VERSION 5.7 ;
  NOWIREEXTENSIONATPIN ON ;
  DIVIDERCHAR "/" ;
  BUSBITCHARS "[]" ;
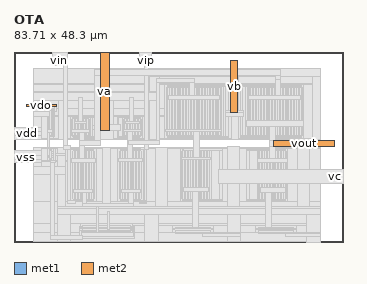
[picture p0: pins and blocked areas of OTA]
MACRO OTA
  CLASS BLOCK ;
  FOREIGN OTA ;
  ORIGIN 1.020 6.080 ;
  SIZE 83.710 BY 48.300 ;
  PIN vdd
    ANTENNADIFFAREA 38.813801 ;
    PORT
      LAYER met1 ;
        RECT 0.950 20.980 1.950 21.980 ;
    END
  END vdd
  PIN vss
    ANTENNADIFFAREA 53.217800 ;
    PORT
      LAYER met1 ;
        RECT 0.980 14.960 1.980 15.960 ;
    END
  END vss
  PIN vip
    ANTENNAGATEAREA 38.399998 ;
    PORT
      LAYER met1 ;
        RECT 31.990 39.990 32.990 40.990 ;
    END
  END vip
  PIN vin
    ANTENNAGATEAREA 38.399998 ;
    PORT
      LAYER met1 ;
        RECT 10.040 40.000 11.040 41.000 ;
    END
  END vin
  PIN vc
    ANTENNAGATEAREA 96.000000 ;
    PORT
      LAYER met1 ;
        RECT 79.970 10.010 80.970 11.010 ;
    END
  END vc
  PIN va
    ANTENNAGATEAREA 19.199999 ;
    PORT
      LAYER met2 ;
        RECT 20.870 22.270 23.230 42.000 ;
    END
  END va
  PIN vb
    ANTENNAGATEAREA 192.000000 ;
    PORT
      LAYER met2 ;
        RECT 54.060 26.800 55.760 40.130 ;
    END
  END vb
  PIN vout
    ANTENNADIFFAREA 59.160000 ;
    PORT
      LAYER met2 ;
        RECT 65.000 18.270 80.580 19.630 ;
    END
  END vout
  PIN vdo
    ANTENNAGATEAREA 2.400000 ;
    PORT
      LAYER met2 ;
        RECT 2.210 28.480 9.710 28.980 ;
    END
  END vdo
  OBS
      LAYER nwell ;
        RECT 7.020 20.005 9.380 28.195 ;
        RECT 12.995 20.005 18.805 26.195 ;
        RECT 26.205 19.995 32.015 26.185 ;
        RECT 36.995 19.995 52.465 34.185 ;
        RECT 57.540 19.995 73.010 34.185 ;
      LAYER pwell ;
        RECT 7.020 14.320 9.380 18.020 ;
        RECT 13.010 3.920 20.200 18.020 ;
        RECT 25.045 3.890 32.235 17.990 ;
        RECT 40.955 3.900 49.525 18.000 ;
        RECT 60.455 3.920 69.025 18.020 ;
        RECT 15.460 -4.090 29.560 -1.040 ;
        RECT 38.880 -4.000 49.980 -1.640 ;
        RECT 60.010 -3.965 71.110 -1.605 ;
      LAYER li1 ;
        RECT 3.990 38.020 7.390 38.030 ;
        RECT 3.990 38.000 37.360 38.020 ;
        RECT 3.990 34.170 76.970 38.000 ;
        RECT 3.990 33.835 76.990 34.170 ;
        RECT 3.990 27.820 37.360 33.835 ;
        RECT 37.975 33.325 38.375 33.495 ;
        RECT 38.665 33.325 39.065 33.495 ;
        RECT 39.355 33.325 39.755 33.495 ;
        RECT 40.045 33.325 40.445 33.495 ;
        RECT 40.735 33.325 41.135 33.495 ;
        RECT 41.425 33.325 41.825 33.495 ;
        RECT 42.115 33.325 42.515 33.495 ;
        RECT 42.805 33.325 43.205 33.495 ;
        RECT 43.495 33.325 43.895 33.495 ;
        RECT 44.185 33.325 44.585 33.495 ;
        RECT 44.875 33.325 45.275 33.495 ;
        RECT 45.565 33.325 45.965 33.495 ;
        RECT 46.255 33.325 46.655 33.495 ;
        RECT 46.945 33.325 47.345 33.495 ;
        RECT 47.635 33.325 48.035 33.495 ;
        RECT 48.325 33.325 48.725 33.495 ;
        RECT 49.015 33.325 49.415 33.495 ;
        RECT 49.705 33.325 50.105 33.495 ;
        RECT 50.395 33.325 50.795 33.495 ;
        RECT 51.085 33.325 51.485 33.495 ;
        RECT 3.990 20.355 7.390 27.820 ;
        RECT 8.000 27.335 8.400 27.505 ;
        RECT 7.770 21.080 7.940 27.120 ;
        RECT 8.460 21.080 8.630 27.120 ;
        RECT 9.000 26.110 37.345 27.820 ;
        RECT 9.000 25.840 37.360 26.110 ;
        RECT 8.000 20.695 8.400 20.865 ;
        RECT 9.000 20.355 13.345 25.840 ;
        RECT 18.440 25.835 37.360 25.840 ;
        RECT 13.975 25.335 14.375 25.505 ;
        RECT 14.665 25.335 15.065 25.505 ;
        RECT 15.355 25.335 15.755 25.505 ;
        RECT 16.045 25.335 16.445 25.505 ;
        RECT 16.735 25.335 17.135 25.505 ;
        RECT 17.425 25.335 17.825 25.505 ;
        RECT 13.745 21.080 13.915 25.120 ;
        RECT 14.435 21.080 14.605 25.120 ;
        RECT 15.125 21.080 15.295 25.120 ;
        RECT 15.815 21.080 15.985 25.120 ;
        RECT 16.505 21.080 16.675 25.120 ;
        RECT 17.195 21.080 17.365 25.120 ;
        RECT 17.885 21.080 18.055 25.120 ;
        RECT 13.975 20.695 14.375 20.865 ;
        RECT 14.665 20.695 15.065 20.865 ;
        RECT 15.355 20.695 15.755 20.865 ;
        RECT 16.045 20.695 16.445 20.865 ;
        RECT 16.735 20.695 17.135 20.865 ;
        RECT 17.425 20.695 17.825 20.865 ;
        RECT 18.440 20.355 26.555 25.835 ;
        RECT 27.185 25.325 27.585 25.495 ;
        RECT 27.875 25.325 28.275 25.495 ;
        RECT 28.565 25.325 28.965 25.495 ;
        RECT 29.255 25.325 29.655 25.495 ;
        RECT 29.945 25.325 30.345 25.495 ;
        RECT 30.635 25.325 31.035 25.495 ;
        RECT 26.955 21.070 27.125 25.110 ;
        RECT 27.645 21.070 27.815 25.110 ;
        RECT 28.335 21.070 28.505 25.110 ;
        RECT 29.025 21.070 29.195 25.110 ;
        RECT 29.715 21.070 29.885 25.110 ;
        RECT 30.405 21.070 30.575 25.110 ;
        RECT 31.095 21.070 31.265 25.110 ;
        RECT 27.185 20.685 27.585 20.855 ;
        RECT 27.875 20.685 28.275 20.855 ;
        RECT 28.565 20.685 28.965 20.855 ;
        RECT 29.255 20.685 29.655 20.855 ;
        RECT 29.945 20.685 30.345 20.855 ;
        RECT 30.635 20.685 31.035 20.855 ;
        RECT 3.990 20.345 26.555 20.355 ;
        RECT 31.630 20.345 37.360 25.835 ;
        RECT 37.745 21.070 37.915 33.110 ;
        RECT 38.435 21.070 38.605 33.110 ;
        RECT 39.125 21.070 39.295 33.110 ;
        RECT 39.815 21.070 39.985 33.110 ;
        RECT 40.505 21.070 40.675 33.110 ;
        RECT 41.195 21.070 41.365 33.110 ;
        RECT 41.885 21.070 42.055 33.110 ;
        RECT 42.575 21.070 42.745 33.110 ;
        RECT 43.265 21.070 43.435 33.110 ;
        RECT 43.955 21.070 44.125 33.110 ;
        RECT 44.645 21.070 44.815 33.110 ;
        RECT 45.335 21.070 45.505 33.110 ;
        RECT 46.025 21.070 46.195 33.110 ;
        RECT 46.715 21.070 46.885 33.110 ;
        RECT 47.405 21.070 47.575 33.110 ;
        RECT 48.095 21.070 48.265 33.110 ;
        RECT 48.785 21.070 48.955 33.110 ;
        RECT 49.475 21.070 49.645 33.110 ;
        RECT 50.165 21.070 50.335 33.110 ;
        RECT 50.855 21.070 51.025 33.110 ;
        RECT 51.545 21.070 51.715 33.110 ;
        RECT 37.975 20.685 38.375 20.855 ;
        RECT 38.665 20.685 39.065 20.855 ;
        RECT 39.355 20.685 39.755 20.855 ;
        RECT 40.045 20.685 40.445 20.855 ;
        RECT 40.735 20.685 41.135 20.855 ;
        RECT 41.425 20.685 41.825 20.855 ;
        RECT 42.115 20.685 42.515 20.855 ;
        RECT 42.805 20.685 43.205 20.855 ;
        RECT 43.495 20.685 43.895 20.855 ;
        RECT 44.185 20.685 44.585 20.855 ;
        RECT 44.875 20.685 45.275 20.855 ;
        RECT 45.565 20.685 45.965 20.855 ;
        RECT 46.255 20.685 46.655 20.855 ;
        RECT 46.945 20.685 47.345 20.855 ;
        RECT 47.635 20.685 48.035 20.855 ;
        RECT 48.325 20.685 48.725 20.855 ;
        RECT 49.015 20.685 49.415 20.855 ;
        RECT 49.705 20.685 50.105 20.855 ;
        RECT 50.395 20.685 50.795 20.855 ;
        RECT 51.085 20.685 51.485 20.855 ;
        RECT 52.110 20.345 57.890 33.835 ;
        RECT 58.520 33.325 58.920 33.495 ;
        RECT 59.210 33.325 59.610 33.495 ;
        RECT 59.900 33.325 60.300 33.495 ;
        RECT 60.590 33.325 60.990 33.495 ;
        RECT 61.280 33.325 61.680 33.495 ;
        RECT 61.970 33.325 62.370 33.495 ;
        RECT 62.660 33.325 63.060 33.495 ;
        RECT 63.350 33.325 63.750 33.495 ;
        RECT 64.040 33.325 64.440 33.495 ;
        RECT 64.730 33.325 65.130 33.495 ;
        RECT 65.420 33.325 65.820 33.495 ;
        RECT 66.110 33.325 66.510 33.495 ;
        RECT 66.800 33.325 67.200 33.495 ;
        RECT 67.490 33.325 67.890 33.495 ;
        RECT 68.180 33.325 68.580 33.495 ;
        RECT 68.870 33.325 69.270 33.495 ;
        RECT 69.560 33.325 69.960 33.495 ;
        RECT 70.250 33.325 70.650 33.495 ;
        RECT 70.940 33.325 71.340 33.495 ;
        RECT 71.630 33.325 72.030 33.495 ;
        RECT 58.290 21.070 58.460 33.110 ;
        RECT 58.980 21.070 59.150 33.110 ;
        RECT 59.670 21.070 59.840 33.110 ;
        RECT 60.360 21.070 60.530 33.110 ;
        RECT 61.050 21.070 61.220 33.110 ;
        RECT 61.740 21.070 61.910 33.110 ;
        RECT 62.430 21.070 62.600 33.110 ;
        RECT 63.120 21.070 63.290 33.110 ;
        RECT 63.810 21.070 63.980 33.110 ;
        RECT 64.500 21.070 64.670 33.110 ;
        RECT 65.190 21.070 65.360 33.110 ;
        RECT 65.880 21.070 66.050 33.110 ;
        RECT 66.570 21.070 66.740 33.110 ;
        RECT 67.260 21.070 67.430 33.110 ;
        RECT 67.950 21.070 68.120 33.110 ;
        RECT 68.640 21.070 68.810 33.110 ;
        RECT 69.330 21.070 69.500 33.110 ;
        RECT 70.020 21.070 70.190 33.110 ;
        RECT 70.710 21.070 70.880 33.110 ;
        RECT 71.400 21.070 71.570 33.110 ;
        RECT 72.090 21.070 72.260 33.110 ;
        RECT 58.520 20.685 58.920 20.855 ;
        RECT 59.210 20.685 59.610 20.855 ;
        RECT 59.900 20.685 60.300 20.855 ;
        RECT 60.590 20.685 60.990 20.855 ;
        RECT 61.280 20.685 61.680 20.855 ;
        RECT 61.970 20.685 62.370 20.855 ;
        RECT 62.660 20.685 63.060 20.855 ;
        RECT 63.350 20.685 63.750 20.855 ;
        RECT 64.040 20.685 64.440 20.855 ;
        RECT 64.730 20.685 65.130 20.855 ;
        RECT 65.420 20.685 65.820 20.855 ;
        RECT 66.110 20.685 66.510 20.855 ;
        RECT 66.800 20.685 67.200 20.855 ;
        RECT 67.490 20.685 67.890 20.855 ;
        RECT 68.180 20.685 68.580 20.855 ;
        RECT 68.870 20.685 69.270 20.855 ;
        RECT 69.560 20.685 69.960 20.855 ;
        RECT 70.250 20.685 70.650 20.855 ;
        RECT 70.940 20.685 71.340 20.855 ;
        RECT 71.630 20.685 72.030 20.855 ;
        RECT 72.590 20.345 76.990 33.835 ;
        RECT 3.990 20.185 76.990 20.345 ;
        RECT 3.990 19.990 7.390 20.185 ;
        RECT 9.000 20.000 13.340 20.185 ;
        RECT 18.440 20.175 76.990 20.185 ;
        RECT 18.440 19.990 26.550 20.175 ;
        RECT 31.630 19.990 37.360 20.175 ;
        RECT 52.110 20.010 57.860 20.175 ;
        RECT 72.590 20.010 76.990 20.175 ;
        RECT 3.990 17.840 7.380 17.980 ;
        RECT 8.990 17.840 13.370 18.010 ;
        RECT 19.830 17.840 25.390 18.020 ;
        RECT 3.990 17.810 25.390 17.840 ;
        RECT 31.850 17.820 41.340 18.020 ;
        RECT 49.210 17.840 60.810 18.050 ;
        RECT 68.630 17.990 70.970 18.010 ;
        RECT 68.630 17.840 77.010 17.990 ;
        RECT 49.210 17.820 77.010 17.840 ;
        RECT 31.850 17.810 77.010 17.820 ;
        RECT 3.990 17.670 77.010 17.810 ;
        RECT 3.990 14.670 7.380 17.670 ;
        RECT 8.000 17.160 8.400 17.330 ;
        RECT 7.770 15.350 7.940 16.990 ;
        RECT 8.460 15.350 8.630 16.990 ;
        RECT 8.000 15.010 8.400 15.180 ;
        RECT 8.990 14.670 13.370 17.670 ;
        RECT 19.830 17.650 60.810 17.670 ;
        RECT 19.830 17.640 41.340 17.650 ;
        RECT 13.990 17.160 14.390 17.330 ;
        RECT 14.680 17.160 15.080 17.330 ;
        RECT 15.370 17.160 15.770 17.330 ;
        RECT 16.060 17.160 16.460 17.330 ;
        RECT 16.750 17.160 17.150 17.330 ;
        RECT 17.440 17.160 17.840 17.330 ;
        RECT 18.130 17.160 18.530 17.330 ;
        RECT 18.820 17.160 19.220 17.330 ;
        RECT 3.990 14.440 13.370 14.670 ;
        RECT 3.990 4.270 13.360 14.440 ;
        RECT 13.760 4.950 13.930 16.990 ;
        RECT 14.450 4.950 14.620 16.990 ;
        RECT 15.140 4.950 15.310 16.990 ;
        RECT 15.830 4.950 16.000 16.990 ;
        RECT 16.520 4.950 16.690 16.990 ;
        RECT 17.210 4.950 17.380 16.990 ;
        RECT 17.900 4.950 18.070 16.990 ;
        RECT 18.590 4.950 18.760 16.990 ;
        RECT 19.280 4.950 19.450 16.990 ;
        RECT 13.990 4.610 14.390 4.780 ;
        RECT 14.680 4.610 15.080 4.780 ;
        RECT 15.370 4.610 15.770 4.780 ;
        RECT 16.060 4.610 16.460 4.780 ;
        RECT 16.750 4.610 17.150 4.780 ;
        RECT 17.440 4.610 17.840 4.780 ;
        RECT 18.130 4.610 18.530 4.780 ;
        RECT 18.820 4.610 19.220 4.780 ;
        RECT 19.830 4.270 25.395 17.640 ;
        RECT 26.025 17.130 26.425 17.300 ;
        RECT 26.715 17.130 27.115 17.300 ;
        RECT 27.405 17.130 27.805 17.300 ;
        RECT 28.095 17.130 28.495 17.300 ;
        RECT 28.785 17.130 29.185 17.300 ;
        RECT 29.475 17.130 29.875 17.300 ;
        RECT 30.165 17.130 30.565 17.300 ;
        RECT 30.855 17.130 31.255 17.300 ;
        RECT 25.795 4.920 25.965 16.960 ;
        RECT 26.485 4.920 26.655 16.960 ;
        RECT 27.175 4.920 27.345 16.960 ;
        RECT 27.865 4.920 28.035 16.960 ;
        RECT 28.555 4.920 28.725 16.960 ;
        RECT 29.245 4.920 29.415 16.960 ;
        RECT 29.935 4.920 30.105 16.960 ;
        RECT 30.625 4.920 30.795 16.960 ;
        RECT 31.315 4.920 31.485 16.960 ;
        RECT 26.025 4.580 26.425 4.750 ;
        RECT 26.715 4.580 27.115 4.750 ;
        RECT 27.405 4.580 27.805 4.750 ;
        RECT 28.095 4.580 28.495 4.750 ;
        RECT 28.785 4.580 29.185 4.750 ;
        RECT 29.475 4.580 29.875 4.750 ;
        RECT 30.165 4.580 30.565 4.750 ;
        RECT 30.855 4.580 31.255 4.750 ;
        RECT 3.990 4.250 25.395 4.270 ;
        RECT 31.850 4.330 41.340 17.640 ;
        RECT 41.935 17.140 42.335 17.310 ;
        RECT 42.625 17.140 43.025 17.310 ;
        RECT 43.315 17.140 43.715 17.310 ;
        RECT 44.005 17.140 44.405 17.310 ;
        RECT 44.695 17.140 45.095 17.310 ;
        RECT 45.385 17.140 45.785 17.310 ;
        RECT 46.075 17.140 46.475 17.310 ;
        RECT 46.765 17.140 47.165 17.310 ;
        RECT 47.455 17.140 47.855 17.310 ;
        RECT 48.145 17.140 48.545 17.310 ;
        RECT 41.705 4.930 41.875 16.970 ;
        RECT 42.395 4.930 42.565 16.970 ;
        RECT 43.085 4.930 43.255 16.970 ;
        RECT 43.775 4.930 43.945 16.970 ;
        RECT 44.465 4.930 44.635 16.970 ;
        RECT 45.155 4.930 45.325 16.970 ;
        RECT 45.845 4.930 46.015 16.970 ;
        RECT 46.535 4.930 46.705 16.970 ;
        RECT 47.225 4.930 47.395 16.970 ;
        RECT 47.915 4.930 48.085 16.970 ;
        RECT 48.605 4.930 48.775 16.970 ;
        RECT 41.935 4.590 42.335 4.760 ;
        RECT 42.625 4.590 43.025 4.760 ;
        RECT 43.315 4.590 43.715 4.760 ;
        RECT 44.005 4.590 44.405 4.760 ;
        RECT 44.695 4.590 45.095 4.760 ;
        RECT 45.385 4.590 45.785 4.760 ;
        RECT 46.075 4.590 46.475 4.760 ;
        RECT 46.765 4.590 47.165 4.760 ;
        RECT 47.455 4.590 47.855 4.760 ;
        RECT 48.145 4.590 48.545 4.760 ;
        RECT 49.175 4.330 60.810 17.650 ;
        RECT 61.435 17.160 61.835 17.330 ;
        RECT 62.125 17.160 62.525 17.330 ;
        RECT 62.815 17.160 63.215 17.330 ;
        RECT 63.505 17.160 63.905 17.330 ;
        RECT 64.195 17.160 64.595 17.330 ;
        RECT 64.885 17.160 65.285 17.330 ;
        RECT 65.575 17.160 65.975 17.330 ;
        RECT 66.265 17.160 66.665 17.330 ;
        RECT 66.955 17.160 67.355 17.330 ;
        RECT 67.645 17.160 68.045 17.330 ;
        RECT 61.205 4.950 61.375 16.990 ;
        RECT 61.895 4.950 62.065 16.990 ;
        RECT 62.585 4.950 62.755 16.990 ;
        RECT 63.275 4.950 63.445 16.990 ;
        RECT 63.965 4.950 64.135 16.990 ;
        RECT 64.655 4.950 64.825 16.990 ;
        RECT 65.345 4.950 65.515 16.990 ;
        RECT 66.035 4.950 66.205 16.990 ;
        RECT 66.725 4.950 66.895 16.990 ;
        RECT 67.415 4.950 67.585 16.990 ;
        RECT 68.105 4.950 68.275 16.990 ;
        RECT 61.435 4.610 61.835 4.780 ;
        RECT 62.125 4.610 62.525 4.780 ;
        RECT 62.815 4.610 63.215 4.780 ;
        RECT 63.505 4.610 63.905 4.780 ;
        RECT 64.195 4.610 64.595 4.780 ;
        RECT 64.885 4.610 65.285 4.780 ;
        RECT 65.575 4.610 65.975 4.780 ;
        RECT 66.265 4.610 66.665 4.780 ;
        RECT 66.955 4.610 67.355 4.780 ;
        RECT 67.645 4.610 68.045 4.780 ;
        RECT 68.630 4.330 77.010 17.670 ;
        RECT 31.850 4.250 77.010 4.330 ;
        RECT 3.990 -1.400 77.010 4.250 ;
        RECT 3.990 -3.720 15.820 -1.400 ;
        RECT 16.490 -1.960 28.530 -1.790 ;
        RECT 29.180 -1.980 77.010 -1.400 ;
        RECT 29.180 -1.990 60.370 -1.980 ;
        RECT 16.150 -2.420 16.320 -2.020 ;
        RECT 28.700 -2.420 28.870 -2.020 ;
        RECT 16.490 -2.650 28.530 -2.480 ;
        RECT 16.150 -3.110 16.320 -2.710 ;
        RECT 28.700 -3.110 28.870 -2.710 ;
        RECT 16.490 -3.340 28.530 -3.170 ;
        RECT 29.180 -3.620 39.240 -1.990 ;
        RECT 39.910 -2.560 48.950 -2.390 ;
        RECT 39.570 -3.020 39.740 -2.620 ;
        RECT 49.120 -3.020 49.290 -2.620 ;
        RECT 39.910 -3.250 48.950 -3.080 ;
        RECT 49.630 -3.615 60.370 -1.990 ;
        RECT 61.040 -2.525 70.080 -2.355 ;
        RECT 60.700 -2.985 60.870 -2.585 ;
        RECT 70.250 -2.985 70.420 -2.585 ;
        RECT 61.040 -3.215 70.080 -3.045 ;
        RECT 70.740 -3.615 77.010 -1.980 ;
        RECT 49.630 -3.620 77.010 -3.615 ;
        RECT 29.180 -3.720 77.010 -3.620 ;
        RECT 3.990 -6.020 77.010 -3.720 ;
        RECT 13.180 -6.030 77.010 -6.020 ;
        RECT 29.180 -6.040 77.010 -6.030 ;
        RECT 70.740 -6.050 77.010 -6.040 ;
      LAYER met1 ;
        RECT 8.980 41.000 12.400 42.010 ;
        RECT 8.980 40.000 10.040 41.000 ;
        RECT 11.040 40.000 12.400 41.000 ;
        RECT 8.980 39.010 12.400 40.000 ;
        RECT 30.970 40.990 33.990 42.000 ;
        RECT 30.970 39.990 31.990 40.990 ;
        RECT 32.990 39.990 33.990 40.990 ;
        RECT 30.970 38.990 33.990 39.990 ;
        RECT 33.520 36.000 76.990 38.060 ;
        RECT 33.550 32.060 35.940 36.000 ;
        RECT 38.060 33.810 53.450 33.925 ;
        RECT 38.050 33.525 53.450 33.810 ;
        RECT 37.995 33.435 53.450 33.525 ;
        RECT 37.995 33.295 38.355 33.435 ;
        RECT 38.685 33.295 39.045 33.435 ;
        RECT 39.375 33.295 39.735 33.435 ;
        RECT 40.065 33.295 40.425 33.435 ;
        RECT 40.755 33.295 41.115 33.435 ;
        RECT 41.445 33.295 41.805 33.435 ;
        RECT 42.135 33.295 42.495 33.435 ;
        RECT 42.825 33.295 43.185 33.435 ;
        RECT 43.515 33.295 43.875 33.435 ;
        RECT 44.205 33.295 44.565 33.435 ;
        RECT 44.895 33.295 45.255 33.435 ;
        RECT 45.585 33.295 45.945 33.435 ;
        RECT 46.275 33.295 46.635 33.435 ;
        RECT 46.965 33.295 47.325 33.435 ;
        RECT 47.655 33.295 48.015 33.435 ;
        RECT 48.345 33.295 48.705 33.435 ;
        RECT 49.035 33.295 49.395 33.435 ;
        RECT 49.725 33.295 50.085 33.435 ;
        RECT 50.415 33.295 50.775 33.435 ;
        RECT 51.105 33.295 51.465 33.435 ;
        RECT 4.130 32.030 35.940 32.060 ;
        RECT 3.980 29.900 35.940 32.030 ;
        RECT 3.980 27.050 6.010 29.900 ;
        RECT 8.020 27.500 8.380 27.535 ;
        RECT 9.210 27.500 9.710 27.670 ;
        RECT 8.020 27.330 9.710 27.500 ;
        RECT 8.020 27.305 8.380 27.330 ;
        RECT 9.200 27.120 9.710 27.330 ;
        RECT 7.740 27.050 7.970 27.100 ;
        RECT 3.980 25.710 7.970 27.050 ;
        RECT 3.980 23.030 6.010 25.710 ;
        RECT -1.020 21.980 6.010 23.030 ;
        RECT -1.020 20.980 0.950 21.980 ;
        RECT 1.950 20.980 6.010 21.980 ;
        RECT 7.740 21.100 7.970 25.710 ;
        RECT 8.430 22.410 8.660 27.100 ;
        RECT 8.260 21.860 8.810 22.410 ;
        RECT 8.430 21.100 8.660 21.860 ;
        RECT 9.200 20.980 9.380 27.120 ;
        RECT -1.020 20.000 6.010 20.980 ;
        RECT 8.020 20.870 8.380 20.895 ;
        RECT 9.120 20.870 9.380 20.980 ;
        RECT 8.020 20.680 9.380 20.870 ;
        RECT 8.020 20.665 8.380 20.680 ;
        RECT -1.020 19.990 4.290 20.000 ;
        RECT 10.270 19.990 12.120 29.900 ;
        RECT 14.060 25.535 19.340 25.740 ;
        RECT 13.995 25.530 19.340 25.535 ;
        RECT 13.995 25.340 17.805 25.530 ;
        RECT 13.995 25.305 14.355 25.340 ;
        RECT 14.685 25.305 15.045 25.340 ;
        RECT 15.375 25.305 15.735 25.340 ;
        RECT 16.065 25.305 16.425 25.340 ;
        RECT 16.755 25.305 17.115 25.340 ;
        RECT 17.445 25.305 17.805 25.340 ;
        RECT 13.715 22.380 13.945 25.100 ;
        RECT 14.405 24.620 14.635 25.100 ;
        RECT 14.280 24.170 14.750 24.620 ;
        RECT 13.590 21.930 14.060 22.380 ;
        RECT 13.715 21.100 13.945 21.930 ;
        RECT 14.405 21.100 14.635 24.170 ;
        RECT 15.095 22.390 15.325 25.100 ;
        RECT 15.785 24.620 16.015 25.100 ;
        RECT 15.650 24.170 16.120 24.620 ;
        RECT 14.940 21.940 15.410 22.390 ;
        RECT 15.095 21.100 15.325 21.940 ;
        RECT 15.785 21.100 16.015 24.170 ;
        RECT 16.475 22.400 16.705 25.100 ;
        RECT 17.165 24.600 17.395 25.100 ;
        RECT 17.030 24.150 17.500 24.600 ;
        RECT 16.340 21.950 16.810 22.400 ;
        RECT 16.475 21.100 16.705 21.950 ;
        RECT 17.165 21.100 17.395 24.150 ;
        RECT 17.855 22.410 18.085 25.100 ;
        RECT 18.980 23.450 19.340 25.530 ;
        RECT 18.980 22.500 20.280 23.450 ;
        RECT 17.730 21.960 18.200 22.410 ;
        RECT 17.855 21.100 18.085 21.960 ;
        RECT 13.995 20.860 14.355 20.895 ;
        RECT 14.685 20.860 15.045 20.895 ;
        RECT 15.375 20.860 15.735 20.895 ;
        RECT 16.065 20.860 16.425 20.895 ;
        RECT 16.755 20.860 17.115 20.895 ;
        RECT 17.445 20.860 17.805 20.895 ;
        RECT 13.995 20.670 17.805 20.860 ;
        RECT 18.980 20.670 19.340 22.500 ;
        RECT 13.995 20.665 19.340 20.670 ;
        RECT 14.050 20.460 19.340 20.665 ;
        RECT 21.070 20.010 24.350 29.900 ;
        RECT 25.230 25.720 27.510 25.740 ;
        RECT 27.960 25.720 28.200 25.730 ;
        RECT 28.650 25.720 28.890 25.730 ;
        RECT 29.340 25.720 29.580 25.730 ;
        RECT 30.030 25.720 30.270 25.730 ;
        RECT 25.230 25.540 30.960 25.720 ;
        RECT 25.230 23.470 25.630 25.540 ;
        RECT 27.170 25.525 30.960 25.540 ;
        RECT 27.170 25.490 31.015 25.525 ;
        RECT 27.205 25.330 31.015 25.490 ;
        RECT 27.205 25.295 27.565 25.330 ;
        RECT 27.895 25.295 28.255 25.330 ;
        RECT 28.585 25.295 28.945 25.330 ;
        RECT 29.275 25.295 29.635 25.330 ;
        RECT 29.965 25.295 30.325 25.330 ;
        RECT 30.655 25.295 31.015 25.330 ;
        RECT 25.040 22.510 25.940 23.470 ;
        RECT 25.230 20.640 25.630 22.510 ;
        RECT 26.925 22.400 27.155 25.090 ;
        RECT 27.615 24.590 27.845 25.090 ;
        RECT 27.480 24.140 27.950 24.590 ;
        RECT 26.790 21.950 27.260 22.400 ;
        RECT 26.925 21.090 27.155 21.950 ;
        RECT 27.615 21.090 27.845 24.140 ;
        RECT 28.305 22.410 28.535 25.090 ;
        RECT 28.995 24.570 29.225 25.090 ;
        RECT 28.860 24.120 29.330 24.570 ;
        RECT 28.170 21.960 28.640 22.410 ;
        RECT 28.305 21.090 28.535 21.960 ;
        RECT 28.995 21.090 29.225 24.120 ;
        RECT 29.685 22.420 29.915 25.090 ;
        RECT 30.375 24.570 30.605 25.090 ;
        RECT 30.250 24.120 30.720 24.570 ;
        RECT 29.560 21.970 30.030 22.420 ;
        RECT 29.685 21.090 29.915 21.970 ;
        RECT 30.375 21.090 30.605 24.120 ;
        RECT 31.065 22.450 31.295 25.090 ;
        RECT 30.940 22.000 31.410 22.450 ;
        RECT 31.065 21.090 31.295 22.000 ;
        RECT 27.205 20.850 27.565 20.885 ;
        RECT 27.895 20.850 28.255 20.885 ;
        RECT 28.585 20.850 28.945 20.885 ;
        RECT 29.275 20.850 29.635 20.885 ;
        RECT 29.965 20.850 30.325 20.885 ;
        RECT 30.655 20.850 31.015 20.885 ;
        RECT 27.205 20.810 31.015 20.850 ;
        RECT 27.190 20.655 31.015 20.810 ;
        RECT 27.190 20.640 30.970 20.655 ;
        RECT 25.230 20.460 30.970 20.640 ;
        RECT 25.230 20.450 27.500 20.460 ;
        RECT 28.650 20.450 28.890 20.460 ;
        RECT 30.710 20.450 30.950 20.460 ;
        RECT 25.230 20.440 27.330 20.450 ;
        RECT 33.550 20.010 35.940 29.900 ;
        RECT 37.715 22.470 37.945 33.090 ;
        RECT 38.405 31.000 38.635 33.090 ;
        RECT 38.240 30.450 38.810 31.000 ;
        RECT 37.650 22.140 37.990 22.470 ;
        RECT 37.715 21.090 37.945 22.140 ;
        RECT 38.405 21.090 38.635 30.450 ;
        RECT 39.095 22.480 39.325 33.090 ;
        RECT 39.785 30.990 40.015 33.090 ;
        RECT 39.610 30.440 40.180 30.990 ;
        RECT 39.030 22.150 39.370 22.480 ;
        RECT 39.095 21.090 39.325 22.150 ;
        RECT 39.785 21.090 40.015 30.440 ;
        RECT 40.475 22.480 40.705 33.090 ;
        RECT 41.165 30.980 41.395 33.090 ;
        RECT 41.000 30.430 41.570 30.980 ;
        RECT 40.420 22.150 40.760 22.480 ;
        RECT 40.475 21.090 40.705 22.150 ;
        RECT 41.165 21.090 41.395 30.430 ;
        RECT 41.855 22.470 42.085 33.090 ;
        RECT 42.545 30.960 42.775 33.090 ;
        RECT 42.350 30.410 42.920 30.960 ;
        RECT 41.790 22.140 42.130 22.470 ;
        RECT 41.855 21.090 42.085 22.140 ;
        RECT 42.545 21.090 42.775 30.410 ;
        RECT 43.235 22.450 43.465 33.090 ;
        RECT 43.925 30.950 44.155 33.090 ;
        RECT 43.780 30.400 44.320 30.950 ;
        RECT 43.180 22.120 43.520 22.450 ;
        RECT 43.235 21.090 43.465 22.120 ;
        RECT 43.925 21.090 44.155 30.400 ;
        RECT 44.615 22.450 44.845 33.090 ;
        RECT 45.305 30.950 45.535 33.090 ;
        RECT 45.120 30.400 45.690 30.950 ;
        RECT 44.560 22.120 44.900 22.450 ;
        RECT 44.615 21.090 44.845 22.120 ;
        RECT 45.305 21.090 45.535 30.400 ;
        RECT 45.995 22.420 46.225 33.090 ;
        RECT 46.685 30.940 46.915 33.090 ;
        RECT 46.525 30.390 47.080 30.940 ;
        RECT 45.940 22.090 46.280 22.420 ;
        RECT 45.995 21.090 46.225 22.090 ;
        RECT 46.685 21.090 46.915 30.390 ;
        RECT 47.375 22.440 47.605 33.090 ;
        RECT 48.065 30.920 48.295 33.090 ;
        RECT 47.880 30.370 48.450 30.920 ;
        RECT 47.320 22.110 47.660 22.440 ;
        RECT 47.375 21.090 47.605 22.110 ;
        RECT 48.065 21.090 48.295 30.370 ;
        RECT 48.755 22.450 48.985 33.090 ;
        RECT 49.445 30.940 49.675 33.090 ;
        RECT 49.260 30.390 49.830 30.940 ;
        RECT 48.700 22.120 49.040 22.450 ;
        RECT 48.755 21.090 48.985 22.120 ;
        RECT 49.445 21.090 49.675 30.390 ;
        RECT 50.135 22.450 50.365 33.090 ;
        RECT 50.825 30.930 51.055 33.090 ;
        RECT 50.645 30.380 51.200 30.930 ;
        RECT 50.080 22.120 50.420 22.450 ;
        RECT 50.135 21.090 50.365 22.120 ;
        RECT 50.825 21.090 51.055 30.380 ;
        RECT 51.515 22.420 51.745 33.090 ;
        RECT 51.460 22.090 51.800 22.420 ;
        RECT 51.515 21.090 51.745 22.090 ;
        RECT 37.995 20.860 38.355 20.885 ;
        RECT 38.685 20.860 39.045 20.885 ;
        RECT 39.375 20.860 39.735 20.885 ;
        RECT 40.065 20.860 40.425 20.885 ;
        RECT 40.755 20.860 41.115 20.885 ;
        RECT 41.445 20.860 41.805 20.885 ;
        RECT 42.135 20.860 42.495 20.885 ;
        RECT 42.825 20.860 43.185 20.885 ;
        RECT 43.515 20.860 43.875 20.885 ;
        RECT 44.205 20.860 44.565 20.885 ;
        RECT 44.895 20.860 45.255 20.885 ;
        RECT 45.585 20.860 45.945 20.885 ;
        RECT 46.275 20.860 46.635 20.885 ;
        RECT 46.965 20.860 47.325 20.885 ;
        RECT 47.655 20.860 48.015 20.885 ;
        RECT 48.345 20.860 48.705 20.885 ;
        RECT 49.035 20.860 49.395 20.885 ;
        RECT 49.725 20.860 50.085 20.885 ;
        RECT 50.415 20.860 50.775 20.885 ;
        RECT 51.105 20.860 51.465 20.885 ;
        RECT 52.650 20.860 53.450 33.435 ;
        RECT 37.995 20.660 53.450 20.860 ;
        RECT 37.995 20.655 53.390 20.660 ;
        RECT 38.050 20.430 53.390 20.655 ;
        RECT 54.170 20.010 56.090 36.000 ;
        RECT 56.610 33.525 71.990 33.815 ;
        RECT 56.610 33.385 72.010 33.525 ;
        RECT 56.610 27.190 57.080 33.385 ;
        RECT 58.540 33.295 58.900 33.385 ;
        RECT 59.230 33.295 59.590 33.385 ;
        RECT 59.920 33.295 60.280 33.385 ;
        RECT 60.610 33.295 60.970 33.385 ;
        RECT 61.300 33.295 61.660 33.385 ;
        RECT 61.990 33.295 62.350 33.385 ;
        RECT 62.680 33.295 63.040 33.385 ;
        RECT 63.370 33.295 63.730 33.385 ;
        RECT 64.060 33.295 64.420 33.385 ;
        RECT 64.750 33.295 65.110 33.385 ;
        RECT 65.440 33.295 65.800 33.385 ;
        RECT 66.130 33.295 66.490 33.385 ;
        RECT 66.820 33.295 67.180 33.385 ;
        RECT 67.510 33.295 67.870 33.385 ;
        RECT 68.200 33.295 68.560 33.385 ;
        RECT 68.890 33.295 69.250 33.385 ;
        RECT 69.580 33.295 69.940 33.385 ;
        RECT 70.270 33.295 70.630 33.385 ;
        RECT 70.960 33.295 71.320 33.385 ;
        RECT 71.650 33.295 72.010 33.385 ;
        RECT 56.610 26.060 57.360 27.190 ;
        RECT 56.610 20.870 57.080 26.060 ;
        RECT 58.260 24.470 58.490 33.090 ;
        RECT 58.950 30.910 59.180 33.090 ;
        RECT 58.770 30.360 59.340 30.910 ;
        RECT 58.090 23.920 58.660 24.470 ;
        RECT 58.260 21.090 58.490 23.920 ;
        RECT 58.950 21.090 59.180 30.360 ;
        RECT 59.640 24.440 59.870 33.090 ;
        RECT 60.330 30.910 60.560 33.090 ;
        RECT 60.160 30.360 60.730 30.910 ;
        RECT 59.450 23.890 60.020 24.440 ;
        RECT 59.640 21.090 59.870 23.890 ;
        RECT 60.330 21.090 60.560 30.360 ;
        RECT 61.020 24.460 61.250 33.090 ;
        RECT 61.710 30.920 61.940 33.090 ;
        RECT 61.540 30.370 62.110 30.920 ;
        RECT 60.850 23.910 61.420 24.460 ;
        RECT 61.020 21.090 61.250 23.910 ;
        RECT 61.710 21.090 61.940 30.370 ;
        RECT 62.400 24.460 62.630 33.090 ;
        RECT 63.090 30.900 63.320 33.090 ;
        RECT 62.920 30.350 63.490 30.900 ;
        RECT 62.210 23.910 62.780 24.460 ;
        RECT 62.400 21.090 62.630 23.910 ;
        RECT 63.090 21.090 63.320 30.350 ;
        RECT 63.780 24.440 64.010 33.090 ;
        RECT 64.470 30.920 64.700 33.090 ;
        RECT 64.300 30.370 64.870 30.920 ;
        RECT 63.615 23.890 64.160 24.440 ;
        RECT 63.780 21.090 64.010 23.890 ;
        RECT 64.470 21.090 64.700 30.370 ;
        RECT 65.160 24.440 65.390 33.090 ;
        RECT 65.850 30.910 66.080 33.090 ;
        RECT 65.670 30.360 66.240 30.910 ;
        RECT 64.990 23.890 65.560 24.440 ;
        RECT 65.160 21.090 65.390 23.890 ;
        RECT 65.850 21.090 66.080 30.360 ;
        RECT 66.540 24.450 66.770 33.090 ;
        RECT 67.230 30.900 67.460 33.090 ;
        RECT 67.045 30.350 67.600 30.900 ;
        RECT 66.360 23.900 66.930 24.450 ;
        RECT 66.540 21.090 66.770 23.900 ;
        RECT 67.230 21.090 67.460 30.350 ;
        RECT 67.920 24.480 68.150 33.090 ;
        RECT 68.610 30.920 68.840 33.090 ;
        RECT 68.450 30.370 69.020 30.920 ;
        RECT 67.750 23.930 68.320 24.480 ;
        RECT 67.920 21.090 68.150 23.930 ;
        RECT 68.610 21.090 68.840 30.370 ;
        RECT 69.300 24.460 69.530 33.090 ;
        RECT 69.990 30.910 70.220 33.090 ;
        RECT 69.820 30.360 70.390 30.910 ;
        RECT 69.130 23.910 69.700 24.460 ;
        RECT 69.300 21.090 69.530 23.910 ;
        RECT 69.990 21.090 70.220 30.360 ;
        RECT 70.680 24.460 70.910 33.090 ;
        RECT 71.370 30.890 71.600 33.090 ;
        RECT 71.200 30.340 71.750 30.890 ;
        RECT 70.480 23.910 71.050 24.460 ;
        RECT 70.680 21.090 70.910 23.910 ;
        RECT 71.370 21.090 71.600 30.340 ;
        RECT 72.060 24.470 72.290 33.090 ;
        RECT 71.890 23.920 72.460 24.470 ;
        RECT 72.060 21.090 72.290 23.920 ;
        RECT 58.540 20.870 58.900 20.885 ;
        RECT 59.230 20.870 59.590 20.885 ;
        RECT 59.920 20.870 60.280 20.885 ;
        RECT 60.610 20.870 60.970 20.885 ;
        RECT 61.300 20.870 61.660 20.885 ;
        RECT 61.990 20.870 62.350 20.885 ;
        RECT 62.680 20.870 63.040 20.885 ;
        RECT 63.370 20.870 63.730 20.885 ;
        RECT 64.060 20.870 64.420 20.885 ;
        RECT 64.750 20.870 65.110 20.885 ;
        RECT 65.440 20.870 65.800 20.885 ;
        RECT 66.130 20.870 66.490 20.885 ;
        RECT 66.820 20.870 67.180 20.885 ;
        RECT 67.510 20.870 67.870 20.885 ;
        RECT 68.200 20.870 68.560 20.885 ;
        RECT 68.890 20.870 69.250 20.885 ;
        RECT 69.580 20.870 69.940 20.885 ;
        RECT 70.270 20.870 70.630 20.885 ;
        RECT 70.960 20.870 71.320 20.885 ;
        RECT 71.650 20.870 72.010 20.885 ;
        RECT 56.610 20.655 72.010 20.870 ;
        RECT 56.610 20.470 71.955 20.655 ;
        RECT 56.615 20.440 71.955 20.470 ;
        RECT 74.980 19.990 76.960 36.000 ;
        RECT 3.990 17.060 5.990 17.950 ;
        RECT 8.250 17.780 8.740 18.020 ;
        RECT 8.030 17.610 8.740 17.780 ;
        RECT 8.030 17.360 8.360 17.610 ;
        RECT 8.020 17.130 8.380 17.360 ;
        RECT -1.020 15.960 5.990 17.060 ;
        RECT 7.740 16.480 7.970 16.970 ;
        RECT 8.430 16.910 8.660 16.970 ;
        RECT 8.430 16.510 9.380 16.910 ;
        RECT 10.070 16.510 12.060 18.040 ;
        RECT -1.020 14.960 0.980 15.960 ;
        RECT 1.980 14.960 5.990 15.960 ;
        RECT 7.550 15.930 8.100 16.480 ;
        RECT 7.740 15.370 7.970 15.930 ;
        RECT 8.430 15.810 12.060 16.510 ;
        RECT 8.430 15.430 9.380 15.810 ;
        RECT 8.430 15.370 8.660 15.430 ;
        RECT 8.020 14.980 8.380 15.210 ;
        RECT -1.020 14.020 5.990 14.960 ;
        RECT 8.030 14.670 8.360 14.980 ;
        RECT 8.030 14.520 8.720 14.670 ;
        RECT 8.230 14.260 8.720 14.520 ;
        RECT 3.990 13.030 5.990 14.020 ;
        RECT 10.070 13.030 12.060 15.810 ;
        RECT 3.990 11.050 12.060 13.030 ;
        RECT 12.650 17.580 14.080 18.010 ;
        RECT 12.650 17.360 19.150 17.580 ;
        RECT 12.650 17.330 19.200 17.360 ;
        RECT 3.990 11.030 12.030 11.050 ;
        RECT 9.980 3.040 12.030 11.030 ;
        RECT 12.650 4.400 13.280 17.330 ;
        RECT 14.010 17.160 19.200 17.330 ;
        RECT 14.010 17.130 14.370 17.160 ;
        RECT 14.700 17.130 15.060 17.160 ;
        RECT 15.390 17.130 15.750 17.160 ;
        RECT 16.080 17.130 16.440 17.160 ;
        RECT 16.770 17.130 17.130 17.160 ;
        RECT 17.460 17.130 17.820 17.160 ;
        RECT 18.150 17.130 18.510 17.160 ;
        RECT 18.840 17.130 19.200 17.160 ;
        RECT 13.730 14.950 13.960 16.970 ;
        RECT 13.590 14.430 14.090 14.950 ;
        RECT 13.730 4.970 13.960 14.430 ;
        RECT 14.420 7.180 14.650 16.970 ;
        RECT 15.110 14.950 15.340 16.970 ;
        RECT 14.970 14.430 15.470 14.950 ;
        RECT 14.270 6.690 14.780 7.180 ;
        RECT 14.420 4.970 14.650 6.690 ;
        RECT 15.110 4.970 15.340 14.430 ;
        RECT 15.800 7.180 16.030 16.970 ;
        RECT 16.490 14.940 16.720 16.970 ;
        RECT 16.350 14.420 16.850 14.940 ;
        RECT 15.660 6.690 16.170 7.180 ;
        RECT 15.800 4.970 16.030 6.690 ;
        RECT 16.490 4.970 16.720 14.420 ;
        RECT 17.180 7.180 17.410 16.970 ;
        RECT 17.870 14.960 18.100 16.970 ;
        RECT 17.730 14.440 18.230 14.960 ;
        RECT 17.040 6.690 17.550 7.180 ;
        RECT 17.180 4.970 17.410 6.690 ;
        RECT 17.870 4.970 18.100 14.440 ;
        RECT 18.560 7.180 18.790 16.970 ;
        RECT 19.250 14.960 19.480 16.970 ;
        RECT 19.080 14.440 19.580 14.960 ;
        RECT 18.420 6.690 18.930 7.180 ;
        RECT 18.560 4.970 18.790 6.690 ;
        RECT 19.250 4.970 19.480 14.440 ;
        RECT 14.010 4.780 14.370 4.810 ;
        RECT 14.700 4.780 15.060 4.810 ;
        RECT 15.390 4.780 15.750 4.810 ;
        RECT 16.080 4.780 16.440 4.810 ;
        RECT 16.770 4.780 17.130 4.810 ;
        RECT 17.460 4.780 17.820 4.810 ;
        RECT 18.150 4.780 18.510 4.810 ;
        RECT 18.840 4.780 19.200 4.810 ;
        RECT 14.010 4.580 19.200 4.780 ;
        RECT 14.060 4.400 19.160 4.580 ;
        RECT 12.650 4.360 19.160 4.400 ;
        RECT 12.650 3.730 14.500 4.360 ;
        RECT 12.670 3.720 14.500 3.730 ;
        RECT 21.540 3.040 23.520 18.020 ;
        RECT 31.070 17.550 32.680 18.020 ;
        RECT 26.090 17.330 32.680 17.550 ;
        RECT 26.045 17.320 32.680 17.330 ;
        RECT 26.045 17.130 31.235 17.320 ;
        RECT 26.045 17.100 26.405 17.130 ;
        RECT 26.735 17.100 27.095 17.130 ;
        RECT 27.425 17.100 27.785 17.130 ;
        RECT 28.115 17.100 28.475 17.130 ;
        RECT 28.805 17.100 29.165 17.130 ;
        RECT 29.495 17.100 29.855 17.130 ;
        RECT 30.185 17.100 30.545 17.130 ;
        RECT 30.875 17.100 31.235 17.130 ;
        RECT 25.765 15.100 25.995 16.940 ;
        RECT 25.620 14.610 26.130 15.100 ;
        RECT 25.765 4.940 25.995 14.610 ;
        RECT 26.455 7.180 26.685 16.940 ;
        RECT 27.145 15.090 27.375 16.940 ;
        RECT 26.970 14.600 27.480 15.090 ;
        RECT 26.300 6.690 26.810 7.180 ;
        RECT 26.455 4.940 26.685 6.690 ;
        RECT 27.145 4.940 27.375 14.600 ;
        RECT 27.835 7.200 28.065 16.940 ;
        RECT 28.525 15.100 28.755 16.940 ;
        RECT 28.380 14.610 28.890 15.100 ;
        RECT 27.680 6.710 28.190 7.200 ;
        RECT 27.835 4.940 28.065 6.710 ;
        RECT 28.525 4.940 28.755 14.610 ;
        RECT 29.215 7.190 29.445 16.940 ;
        RECT 29.905 15.090 30.135 16.940 ;
        RECT 29.730 14.600 30.240 15.090 ;
        RECT 29.070 6.700 29.580 7.190 ;
        RECT 29.215 4.940 29.445 6.700 ;
        RECT 29.905 4.940 30.135 14.600 ;
        RECT 30.595 7.200 30.825 16.940 ;
        RECT 31.285 15.100 31.515 16.940 ;
        RECT 31.100 14.610 31.610 15.100 ;
        RECT 30.460 6.710 30.970 7.200 ;
        RECT 30.595 4.940 30.825 6.710 ;
        RECT 31.285 4.940 31.515 14.610 ;
        RECT 26.045 4.750 26.405 4.780 ;
        RECT 26.735 4.750 27.095 4.780 ;
        RECT 27.425 4.750 27.785 4.780 ;
        RECT 28.115 4.750 28.475 4.780 ;
        RECT 28.805 4.750 29.165 4.780 ;
        RECT 29.495 4.750 29.855 4.780 ;
        RECT 30.185 4.750 30.545 4.780 ;
        RECT 30.875 4.750 31.235 4.780 ;
        RECT 26.045 4.560 31.235 4.750 ;
        RECT 26.045 4.550 31.530 4.560 ;
        RECT 26.100 4.390 31.530 4.550 ;
        RECT 32.190 4.390 32.680 17.320 ;
        RECT 26.100 4.350 32.680 4.390 ;
        RECT 26.110 4.330 32.680 4.350 ;
        RECT 30.770 4.010 32.680 4.330 ;
        RECT 30.770 3.710 32.600 4.010 ;
        RECT 34.930 3.040 38.000 18.020 ;
        RECT 41.950 17.715 42.120 17.730 ;
        RECT 41.950 17.290 52.000 17.715 ;
        RECT 41.955 17.275 52.000 17.290 ;
        RECT 41.955 17.110 42.315 17.275 ;
        RECT 42.645 17.110 43.005 17.275 ;
        RECT 43.335 17.110 43.695 17.275 ;
        RECT 44.025 17.110 44.385 17.275 ;
        RECT 44.715 17.110 45.075 17.275 ;
        RECT 45.405 17.110 45.765 17.275 ;
        RECT 46.095 17.110 46.455 17.275 ;
        RECT 46.785 17.110 47.145 17.275 ;
        RECT 47.475 17.110 47.835 17.275 ;
        RECT 48.165 17.110 48.525 17.275 ;
        RECT 41.675 15.350 41.905 16.950 ;
        RECT 41.630 15.020 41.970 15.350 ;
        RECT 41.675 4.950 41.905 15.020 ;
        RECT 42.365 7.570 42.595 16.950 ;
        RECT 43.055 15.340 43.285 16.950 ;
        RECT 43.000 15.010 43.340 15.340 ;
        RECT 42.180 7.020 42.750 7.570 ;
        RECT 42.365 4.950 42.595 7.020 ;
        RECT 43.055 4.950 43.285 15.010 ;
        RECT 43.745 7.570 43.975 16.950 ;
        RECT 44.435 15.340 44.665 16.950 ;
        RECT 44.380 15.010 44.720 15.340 ;
        RECT 43.570 7.020 44.140 7.570 ;
        RECT 43.745 4.950 43.975 7.020 ;
        RECT 44.435 4.950 44.665 15.010 ;
        RECT 45.125 7.560 45.355 16.950 ;
        RECT 45.815 15.340 46.045 16.950 ;
        RECT 45.760 15.010 46.100 15.340 ;
        RECT 44.975 7.010 45.505 7.560 ;
        RECT 45.125 4.950 45.355 7.010 ;
        RECT 45.815 4.950 46.045 15.010 ;
        RECT 46.505 7.580 46.735 16.950 ;
        RECT 47.195 15.330 47.425 16.950 ;
        RECT 47.140 15.000 47.480 15.330 ;
        RECT 46.350 7.030 46.890 7.580 ;
        RECT 46.505 4.950 46.735 7.030 ;
        RECT 47.195 4.950 47.425 15.000 ;
        RECT 47.885 7.600 48.115 16.950 ;
        RECT 48.575 15.310 48.805 16.950 ;
        RECT 48.520 14.980 48.860 15.310 ;
        RECT 47.690 7.050 48.260 7.600 ;
        RECT 47.885 4.950 48.115 7.050 ;
        RECT 48.575 4.950 48.805 14.980 ;
        RECT 41.955 4.680 42.315 4.790 ;
        RECT 42.645 4.680 43.005 4.790 ;
        RECT 43.335 4.680 43.695 4.790 ;
        RECT 44.025 4.680 44.385 4.790 ;
        RECT 44.715 4.680 45.075 4.790 ;
        RECT 45.405 4.680 45.765 4.790 ;
        RECT 46.095 4.680 46.455 4.790 ;
        RECT 46.785 4.680 47.145 4.790 ;
        RECT 47.475 4.680 47.835 4.790 ;
        RECT 48.165 4.680 48.525 4.790 ;
        RECT 51.120 4.680 52.000 17.275 ;
        RECT 41.955 4.560 52.000 4.680 ;
        RECT 42.010 4.240 52.000 4.560 ;
        RECT 51.120 4.230 52.000 4.240 ;
        RECT 53.350 3.040 56.420 18.080 ;
        RECT 57.970 17.360 68.005 17.720 ;
        RECT 57.970 17.280 68.025 17.360 ;
        RECT 57.970 4.690 58.850 17.280 ;
        RECT 61.455 17.130 61.815 17.280 ;
        RECT 62.145 17.130 62.505 17.280 ;
        RECT 62.835 17.130 63.195 17.280 ;
        RECT 63.525 17.130 63.885 17.280 ;
        RECT 64.215 17.130 64.575 17.280 ;
        RECT 64.905 17.130 65.265 17.280 ;
        RECT 65.595 17.130 65.955 17.280 ;
        RECT 66.285 17.130 66.645 17.280 ;
        RECT 66.975 17.130 67.335 17.280 ;
        RECT 67.665 17.130 68.025 17.280 ;
        RECT 61.175 15.010 61.405 16.970 ;
        RECT 61.000 14.460 61.570 15.010 ;
        RECT 61.175 4.970 61.405 14.460 ;
        RECT 61.865 7.460 62.095 16.970 ;
        RECT 62.555 15.010 62.785 16.970 ;
        RECT 62.390 14.460 62.960 15.010 ;
        RECT 61.700 6.910 62.270 7.460 ;
        RECT 61.865 4.970 62.095 6.910 ;
        RECT 62.555 4.970 62.785 14.460 ;
        RECT 63.245 7.480 63.475 16.970 ;
        RECT 63.935 15.010 64.165 16.970 ;
        RECT 63.740 14.460 64.310 15.010 ;
        RECT 63.020 6.930 63.590 7.480 ;
        RECT 63.245 4.970 63.475 6.930 ;
        RECT 63.935 4.970 64.165 14.460 ;
        RECT 64.625 7.500 64.855 16.970 ;
        RECT 65.315 15.000 65.545 16.970 ;
        RECT 65.120 14.450 65.690 15.000 ;
        RECT 64.430 6.950 65.000 7.500 ;
        RECT 64.625 4.970 64.855 6.950 ;
        RECT 65.315 4.970 65.545 14.450 ;
        RECT 66.005 7.490 66.235 16.970 ;
        RECT 66.695 15.010 66.925 16.970 ;
        RECT 66.530 14.460 67.100 15.010 ;
        RECT 65.840 6.940 66.410 7.490 ;
        RECT 66.005 4.970 66.235 6.940 ;
        RECT 66.695 4.970 66.925 14.460 ;
        RECT 67.385 7.470 67.615 16.970 ;
        RECT 68.075 15.010 68.305 16.970 ;
        RECT 67.900 14.460 68.470 15.010 ;
        RECT 67.210 6.920 67.780 7.470 ;
        RECT 67.385 4.970 67.615 6.920 ;
        RECT 68.075 4.970 68.305 14.460 ;
        RECT 61.455 4.690 61.815 4.810 ;
        RECT 62.145 4.690 62.505 4.810 ;
        RECT 62.835 4.690 63.195 4.810 ;
        RECT 63.525 4.690 63.885 4.810 ;
        RECT 64.215 4.690 64.575 4.810 ;
        RECT 64.905 4.690 65.265 4.810 ;
        RECT 65.595 4.690 65.955 4.810 ;
        RECT 66.285 4.690 66.645 4.810 ;
        RECT 66.975 4.690 67.335 4.810 ;
        RECT 67.665 4.690 68.025 4.810 ;
        RECT 57.970 4.580 68.025 4.690 ;
        RECT 57.970 4.250 67.970 4.580 ;
        RECT 57.970 4.230 58.850 4.250 ;
        RECT 71.090 3.040 74.160 17.990 ;
        RECT 78.960 11.010 81.970 12.040 ;
        RECT 78.960 10.010 79.970 11.010 ;
        RECT 80.970 10.010 81.970 11.010 ;
        RECT 78.960 9.010 81.970 10.010 ;
        RECT 9.980 2.380 76.960 3.040 ;
        RECT 9.970 1.000 76.960 2.380 ;
        RECT 9.970 -6.040 13.440 1.000 ;
        RECT 19.930 -1.760 20.460 -1.600 ;
        RECT 16.510 -1.990 28.510 -1.760 ;
        RECT 16.120 -2.050 16.350 -2.040 ;
        RECT 15.620 -2.400 16.350 -2.050 ;
        RECT 19.930 -2.130 20.460 -1.990 ;
        RECT 28.670 -2.090 28.900 -2.040 ;
        RECT 15.620 -2.730 16.170 -2.400 ;
        RECT 22.720 -2.450 23.250 -2.290 ;
        RECT 28.670 -2.340 29.500 -2.090 ;
        RECT 28.670 -2.400 28.900 -2.340 ;
        RECT 16.510 -2.680 28.510 -2.450 ;
        RECT 15.620 -3.090 16.350 -2.730 ;
        RECT 22.720 -2.820 23.250 -2.680 ;
        RECT 28.670 -2.780 28.900 -2.730 ;
        RECT 29.240 -2.780 29.500 -2.340 ;
        RECT 15.620 -4.600 16.170 -3.090 ;
        RECT 19.920 -3.140 20.450 -3.010 ;
        RECT 28.670 -3.030 29.500 -2.780 ;
        RECT 28.670 -3.090 28.900 -3.030 ;
        RECT 16.510 -3.370 28.510 -3.140 ;
        RECT 19.920 -3.540 20.450 -3.370 ;
        RECT 29.240 -4.600 29.500 -3.030 ;
        RECT 15.620 -5.280 29.500 -4.600 ;
        RECT 32.220 -5.910 35.690 1.000 ;
        RECT 44.410 -2.360 45.840 -1.480 ;
        RECT 39.930 -2.590 48.930 -2.360 ;
        RECT 39.490 -2.640 39.760 -2.620 ;
        RECT 49.100 -2.640 49.370 -2.620 ;
        RECT 39.490 -3.000 39.770 -2.640 ;
        RECT 49.090 -3.000 49.370 -2.640 ;
        RECT 39.490 -3.020 39.760 -3.000 ;
        RECT 49.100 -3.020 49.370 -3.000 ;
        RECT 39.930 -3.280 48.930 -3.050 ;
        RECT 39.980 -3.770 48.870 -3.280 ;
        RECT 53.130 -3.770 56.600 1.000 ;
        RECT 62.990 -2.325 64.420 -1.440 ;
        RECT 61.060 -2.555 70.060 -2.325 ;
        RECT 60.620 -2.605 60.890 -2.590 ;
        RECT 70.240 -2.605 70.500 -2.590 ;
        RECT 60.620 -2.965 60.900 -2.605 ;
        RECT 70.220 -2.965 70.500 -2.605 ;
        RECT 60.620 -2.985 60.890 -2.965 ;
        RECT 70.240 -2.980 70.500 -2.965 ;
        RECT 61.060 -3.245 70.060 -3.015 ;
        RECT 39.980 -3.960 56.600 -3.770 ;
        RECT 61.130 -3.690 70.020 -3.245 ;
        RECT 73.440 -3.690 76.910 1.000 ;
        RECT 61.130 -3.930 76.910 -3.690 ;
        RECT 46.810 -4.660 56.600 -3.960 ;
        RECT 68.030 -4.610 76.910 -3.930 ;
        RECT 53.130 -6.040 56.600 -4.660 ;
        RECT 73.440 -6.080 76.910 -4.610 ;
      LAYER met2 ;
        RECT 8.730 38.700 12.580 42.220 ;
        RECT 30.950 38.990 33.980 42.000 ;
        RECT 10.830 38.690 12.580 38.700 ;
        RECT 9.200 27.130 9.710 28.480 ;
        RECT 7.550 21.850 8.820 22.420 ;
        RECT 7.550 18.030 8.130 21.850 ;
        RECT 11.470 18.520 12.580 38.690 ;
        RECT 15.410 24.640 16.500 30.700 ;
        RECT 14.260 24.110 17.510 24.640 ;
        RECT 28.360 24.630 29.450 30.680 ;
        RECT 27.420 24.080 30.770 24.630 ;
        RECT 13.560 21.880 18.220 22.470 ;
        RECT 19.460 22.270 20.870 23.670 ;
        RECT 23.230 22.270 25.930 23.670 ;
        RECT 26.760 21.910 31.420 22.500 ;
        RECT 7.550 18.020 8.740 18.030 ;
        RECT 7.550 17.610 9.420 18.020 ;
        RECT 7.550 15.930 8.130 17.610 ;
        RECT 9.040 14.670 9.420 17.610 ;
        RECT 11.470 17.310 13.390 18.520 ;
        RECT 15.740 15.130 16.960 21.880 ;
        RECT 27.950 15.210 29.010 21.910 ;
        RECT 32.060 17.320 33.170 38.990 ;
        RECT 43.490 31.210 44.960 35.510 ;
        RECT 38.170 30.130 51.290 31.210 ;
        RECT 65.460 31.190 66.680 36.330 ;
        RECT 58.640 30.050 71.840 31.190 ;
        RECT 52.650 26.800 54.060 27.290 ;
        RECT 55.760 26.800 57.410 27.290 ;
        RECT 52.650 25.940 57.410 26.800 ;
        RECT 57.990 23.240 72.700 24.930 ;
        RECT 37.600 22.060 51.840 22.540 ;
        RECT 44.700 15.440 46.190 22.060 ;
        RECT 63.830 19.630 65.530 23.240 ;
        RECT 63.830 18.270 65.000 19.630 ;
        RECT 8.230 14.250 9.420 14.670 ;
        RECT 8.290 -4.540 9.300 14.250 ;
        RECT 13.580 14.240 19.600 15.130 ;
        RECT 25.550 14.410 31.640 15.210 ;
        RECT 41.580 14.950 48.910 15.440 ;
        RECT 63.830 15.270 65.530 18.270 ;
        RECT 60.910 14.070 68.570 15.270 ;
        RECT 51.030 8.700 82.690 12.470 ;
        RECT 14.230 6.480 18.980 7.310 ;
        RECT 26.230 6.480 31.040 7.320 ;
        RECT 42.010 6.680 48.380 7.790 ;
        RECT 16.280 3.730 17.470 6.480 ;
        RECT 28.070 3.730 29.260 6.480 ;
        RECT 16.280 2.850 29.260 3.730 ;
        RECT 19.840 -3.570 20.530 2.850 ;
        RECT 22.650 -2.880 23.350 1.590 ;
        RECT 44.450 -2.470 45.930 6.680 ;
        RECT 61.550 6.630 67.920 7.740 ;
        RECT 62.990 -2.510 64.470 6.630 ;
        RECT 8.290 -5.350 16.330 -4.540 ;
      LAYER met3 ;
        RECT 19.570 36.200 66.670 37.680 ;
        RECT 19.570 19.610 21.020 36.200 ;
        RECT 35.630 35.510 44.920 35.520 ;
        RECT 35.080 34.490 44.920 35.510 ;
        RECT 65.410 35.270 66.670 36.200 ;
        RECT 35.080 19.630 36.030 34.490 ;
        RECT 15.720 18.530 21.020 19.610 ;
        RECT 28.010 18.610 36.030 19.630 ;
        RECT 28.010 18.590 35.820 18.610 ;
        RECT 17.850 18.510 21.020 18.530 ;
  END
END OTA
END LIBRARY

